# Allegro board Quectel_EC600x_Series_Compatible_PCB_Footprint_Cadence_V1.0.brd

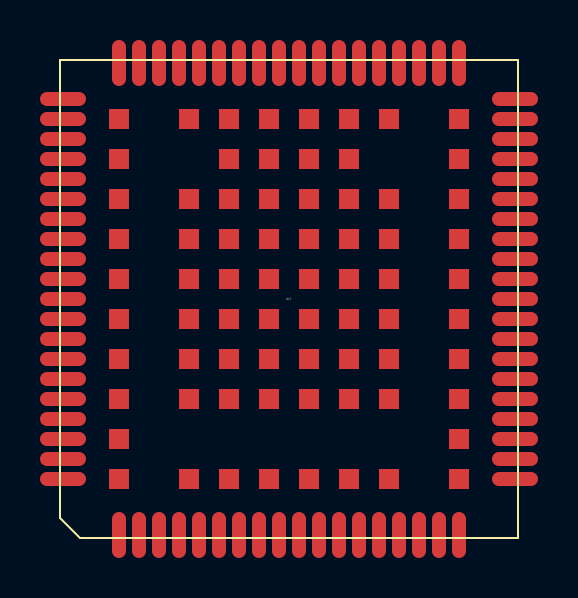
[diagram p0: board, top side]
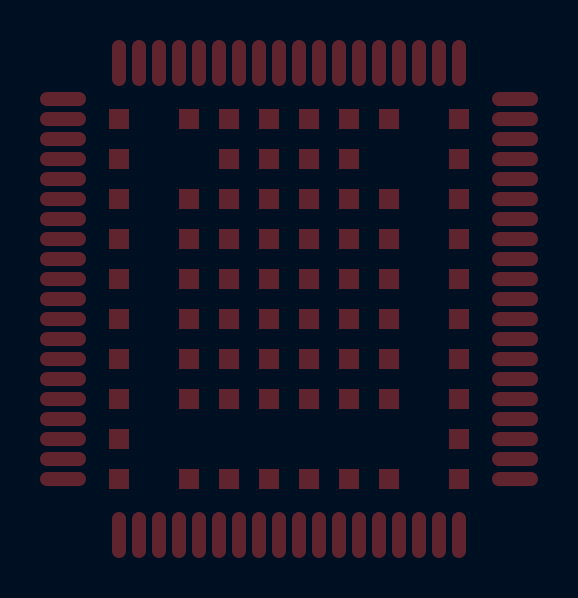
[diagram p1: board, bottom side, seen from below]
No outline. copper layers: TOP, BOTTOM. Coordinates in mm from the lowest, leftmost part position.

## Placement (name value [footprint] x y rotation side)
REF  -  [unnamed]  0 0 0 top

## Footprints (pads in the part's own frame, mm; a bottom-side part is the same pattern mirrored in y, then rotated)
unnamed
  oval 0.7x2.3 smd: 1(-8.5,-11.8) 2(-7.5,-11.8) 3(-6.5,-11.8) 4(-5.5,-11.8) 5(-4.5,-11.8) 6(-3.5,-11.8) 7(-2.5,-11.8) 8(-1.5,-11.8) 9(-0.5,-11.8) 10(0.5,-11.8) 11(1.5,-11.8) 12(2.5,-11.8) 13(3.5,-11.8) 14(4.5,-11.8) 15(5.5,-11.8) 16(6.5,-11.8) 17(7.5,-11.8) 18(8.5,-11.8) 39(8.5,11.8) 40(7.5,11.8) 41(6.5,11.8) 42(5.5,11.8) 43(4.5,11.8) 44(3.5,11.8) 45(2.5,11.8) 46(1.5,11.8) 47(0.5,11.8) 48(-0.5,11.8) 49(-1.5,11.8) 50(-2.5,11.8) 51(-3.5,11.8) 52(-4.5,11.8) 53(-5.5,11.8) 54(-6.5,11.8) 55(-7.5,11.8) 56(-8.5,11.8)
  oval 2.3x0.7 smd: 19(11.3,-9) 20(11.3,-8) 21(11.3,-7) 22(11.3,-6) 23(11.3,-5) 24(11.3,-4) 25(11.3,-3) 26(11.3,-2) 27(11.3,-1) 28(11.3,0) 29(11.3,1) 30(11.3,2) 31(11.3,3) 32(11.3,4) 33(11.3,5) 34(11.3,6) 35(11.3,7) 36(11.3,8) 37(11.3,9) 38(11.3,10) 57(-11.3,10) 58(-11.3,9) 59(-11.3,8) 60(-11.3,7) 61(-11.3,6) 62(-11.3,5) 63(-11.3,4) 64(-11.3,3) 65(-11.3,2) 66(-11.3,1) 67(-11.3,0) 68(-11.3,-1) 69(-11.3,-2) 70(-11.3,-3) 71(-11.3,-4) 72(-11.3,-5) 73(-11.3,-6) 74(-11.3,-7) 75(-11.3,-8) 76(-11.3,-9)
  rect 1x1 smd: 77(-3,-3) 78(-1,-3) 79(1,-3) 80(3,-3) 81(3,-1) 82(3,1) 83(3,3) 84(1,3) 85(-1,3) 86(-3,3) 87(-3,1) 88(-3,-1) 89(-1,-1) 90(1,-1) 91(1,1) 92(-1,1) 93(-5,-5) 94(-3,-5) 95(-1,-5) 96(1,-5) 97(3,-5) 98(5,-5) 99(5,-3) 100(5,-1) 101(5,1) 102(5,3) 103(5,5) 104(3,5) 105(1,5) 106(-1,5) 107(-3,5) 108(-5,5) 109(-5,3) 110(-5,1) 111(-5,-1) 112(-5,-3) 113(-8.5,-9) 114(-5,-9) 115(-3,-9) 116(-1,-9) 117(1,-9) 118(3,-9) 119(5,-9) 120(8.5,-9) 121(8.5,-7) 122(8.5,-5) 123(8.5,-3) 124(8.5,-1) 125(8.5,1) 126(8.5,3) 127(8.5,5) 128(8.5,7) 129(8.5,9) 130(5,9) 131(3,9) 132(1,9) 133(-1,9) 134(-3,9) 135(-5,9) 136(-8.5,9) 137(-8.5,7) 138(-8.5,5) 139(-8.5,3) 140(-8.5,1) 141(-8.5,-1) 142(-8.5,-3) 143(-8.5,-5) 144(-8.5,-7) 145(3,7) 146(1,7) 147(-1,7) 148(-3,7)

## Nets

Pads without a net: REF 1 2 3 4 5 6 7 8 9 10 11 12 13 14 15 16 17 18 19 20 21 22 23 24 25 26 27 28 29 30 31 32 33 34 35 36 37 38 39 40 41 42 43 44 45 46 47 48 49 50 51 52 53 54 55 56 57 58 59 60 61 62 63 64 65 66 67 68 69 70 71 72 73 74 75 76 77 78 79 80 81 82 83 84 85 86 87 88 89 90 91 92 93 94 95 96 97 98 99 100 101 102 103 104 105 106 107 108 109 110 111 112 113 114 115 116 117 118 119 120 121 122 123 124 125 126 127 128 129 130 131 132 133 134 135 136 137 138 139 140 141 142 143 144 145 146 147 148
